VERSION 5.8 ;
BUSBITCHARS "[]" ;
DIVIDERCHAR "/" ;
UNITS
    DATABASE MICRONS 1000 ;
END UNITS

VIA PLL_RING_DCO_PHYS_via1_2_2200_440_1_5_410_410
  VIARULE via1Array ;
  CUTSIZE 0.19 0.19 ;
  LAYERS Metal1 Via1 Metal2 ;
  CUTSPACING 0.22 0.22 ;
  ENCLOSURE 0.05 0.125 0.005 0.05 ;
  ROWCOL 1 5 ;
END PLL_RING_DCO_PHYS_via1_2_2200_440_1_5_410_410

VIA PLL_RING_DCO_PHYS_via2_3_2200_440_1_5_410_410
  VIARULE via2Array ;
  CUTSIZE 0.19 0.19 ;
  LAYERS Metal2 Via2 Metal3 ;
  CUTSPACING 0.22 0.22 ;
  ENCLOSURE 0.005 0.05 0.05 0.005 ;
  ROWCOL 1 5 ;
END PLL_RING_DCO_PHYS_via2_3_2200_440_1_5_410_410

VIA PLL_RING_DCO_PHYS_via3_4_2200_440_1_5_410_410
  VIARULE via3Array ;
  CUTSIZE 0.19 0.19 ;
  LAYERS Metal3 Via3 Metal4 ;
  CUTSPACING 0.22 0.22 ;
  ENCLOSURE 0.05 0.005 0.005 0.05 ;
  ROWCOL 1 5 ;
END PLL_RING_DCO_PHYS_via3_4_2200_440_1_5_410_410

VIA PLL_RING_DCO_PHYS_via4_5_2200_440_1_5_410_410
  VIARULE via4Array ;
  CUTSIZE 0.19 0.19 ;
  LAYERS Metal4 Via4 Metal5 ;
  CUTSPACING 0.22 0.22 ;
  ENCLOSURE 0.005 0.05 0.05 0.005 ;
  ROWCOL 1 5 ;
END PLL_RING_DCO_PHYS_via4_5_2200_440_1_5_410_410

VIA PLL_RING_DCO_PHYS_via5_6_2200_440_1_2_840_840
  VIARULE viaTop1Array ;
  CUTSIZE 0.42 0.42 ;
  LAYERS Metal5 TopVia1 TopMetal1 ;
  CUTSPACING 0.42 0.42 ;
  ENCLOSURE 0.1 0.1 0.47 0.42 ;
  ROWCOL 1 2 ;
END PLL_RING_DCO_PHYS_via5_6_2200_440_1_2_840_840

VIA PLL_RING_DCO_PHYS_via6_7_5000_5000_2_2_1960_1960
  VIARULE viaTop2Array ;
  CUTSIZE 0.9 0.9 ;
  LAYERS TopMetal1 TopVia2 TopMetal2 ;
  CUTSPACING 1.06 1.06 ;
  ENCLOSURE 1.07 0.5 0.5 1.07 ;
  ROWCOL 2 2 ;
END PLL_RING_DCO_PHYS_via6_7_5000_5000_2_2_1960_1960

VIA PLL_RING_DCO_PHYS_via6_7_5000_2200_1_2_1960_1960
  VIARULE viaTop2Array ;
  CUTSIZE 0.9 0.9 ;
  LAYERS TopMetal1 TopVia2 TopMetal2 ;
  CUTSPACING 1.06 1.06 ;
  ENCLOSURE 1.07 0.5 0.5 0.65 ;
  ROWCOL 1 2 ;
END PLL_RING_DCO_PHYS_via6_7_5000_2200_1_2_1960_1960

VIA PLL_RING_DCO_PHYS_via6_7_2200_5000_2_1_1960_1960
  VIARULE viaTop2Array ;
  CUTSIZE 0.9 0.9 ;
  LAYERS TopMetal1 TopVia2 TopMetal2 ;
  CUTSPACING 1.06 1.06 ;
  ENCLOSURE 0.65 0.5 0.5 1.07 ;
  ROWCOL 2 1 ;
END PLL_RING_DCO_PHYS_via6_7_2200_5000_2_1_1960_1960

VIA PLL_RING_DCO_PHYS_via6_7_2200_2200_1_1_1960_1960
  VIARULE viaTop2Array ;
  CUTSIZE 0.9 0.9 ;
  LAYERS TopMetal1 TopVia2 TopMetal2 ;
  CUTSPACING 1.06 1.06 ;
  ENCLOSURE 0.65 0.5 0.5 0.65 ;
END PLL_RING_DCO_PHYS_via6_7_2200_2200_1_1_1960_1960

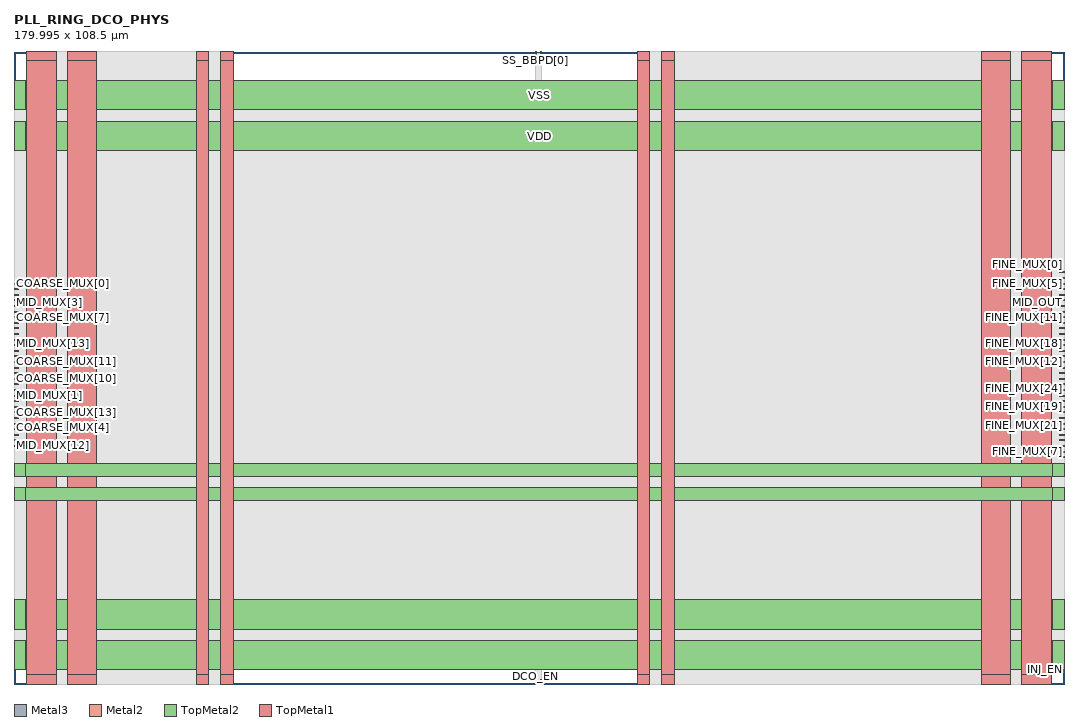
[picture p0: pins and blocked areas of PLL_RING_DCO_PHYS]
MACRO PLL_RING_DCO_PHYS
  FOREIGN PLL_RING_DCO_PHYS 0 0 ;
  CLASS BLOCK ;
  SIZE 179.995 BY 108.5 ;
  PIN COARSE_MUX[0]
    DIRECTION INPUT ;
    USE SIGNAL ;
    PORT
      LAYER Metal3 ;
        RECT  0 68.54 0.72 68.74 ;
    END
  END COARSE_MUX[0]
  PIN COARSE_MUX[10]
    DIRECTION INPUT ;
    USE SIGNAL ;
    PORT
      LAYER Metal3 ;
        RECT  0 52.22 0.72 52.42 ;
    END
  END COARSE_MUX[10]
  PIN COARSE_MUX[11]
    DIRECTION INPUT ;
    USE SIGNAL ;
    PORT
      LAYER Metal3 ;
        RECT  0 55.1 0.72 55.3 ;
    END
  END COARSE_MUX[11]
  PIN COARSE_MUX[12]
    DIRECTION INPUT ;
    USE SIGNAL ;
    PORT
      LAYER Metal3 ;
        RECT  0 56.06 0.72 56.26 ;
    END
  END COARSE_MUX[12]
  PIN COARSE_MUX[13]
    DIRECTION INPUT ;
    USE SIGNAL ;
    PORT
      LAYER Metal3 ;
        RECT  0 46.46 0.72 46.66 ;
    END
  END COARSE_MUX[13]
  PIN COARSE_MUX[14]
    DIRECTION INPUT ;
    USE SIGNAL ;
    PORT
      LAYER Metal3 ;
        RECT  0 53.18 0.72 53.38 ;
    END
  END COARSE_MUX[14]
  PIN COARSE_MUX[1]
    DIRECTION INPUT ;
    USE SIGNAL ;
    PORT
      LAYER Metal3 ;
        RECT  0 45.5 0.72 45.7 ;
    END
  END COARSE_MUX[1]
  PIN COARSE_MUX[2]
    DIRECTION INPUT ;
    USE SIGNAL ;
    PORT
      LAYER Metal3 ;
        RECT  0 58.94 0.72 59.14 ;
    END
  END COARSE_MUX[2]
  PIN COARSE_MUX[3]
    DIRECTION INPUT ;
    USE SIGNAL ;
    PORT
      LAYER Metal3 ;
        RECT  0 59.9 0.72 60.1 ;
    END
  END COARSE_MUX[3]
  PIN COARSE_MUX[4]
    DIRECTION INPUT ;
    USE SIGNAL ;
    PORT
      LAYER Metal3 ;
        RECT  0 42.62 0.72 42.82 ;
    END
  END COARSE_MUX[4]
  PIN COARSE_MUX[5]
    DIRECTION INPUT ;
    USE SIGNAL ;
    PORT
      LAYER Metal3 ;
        RECT  0 60.86 0.72 61.06 ;
    END
  END COARSE_MUX[5]
  PIN COARSE_MUX[6]
    DIRECTION INPUT ;
    USE SIGNAL ;
    PORT
      LAYER Metal3 ;
        RECT  0 50.3 0.72 50.5 ;
    END
  END COARSE_MUX[6]
  PIN COARSE_MUX[7]
    DIRECTION INPUT ;
    USE SIGNAL ;
    PORT
      LAYER Metal3 ;
        RECT  0 62.78 0.72 62.98 ;
    END
  END COARSE_MUX[7]
  PIN COARSE_MUX[8]
    DIRECTION INPUT ;
    USE SIGNAL ;
    PORT
      LAYER Metal3 ;
        RECT  0 51.26 0.72 51.46 ;
    END
  END COARSE_MUX[8]
  PIN COARSE_MUX[9]
    DIRECTION INPUT ;
    USE SIGNAL ;
    PORT
      LAYER Metal3 ;
        RECT  0 63.74 0.72 63.94 ;
    END
  END COARSE_MUX[9]
  PIN DCO_EN
    DIRECTION INPUT ;
    USE SIGNAL ;
    PORT
      LAYER Metal2 ;
        RECT  89.36 0 89.56 0.72 ;
    END
  END DCO_EN
  PIN FINE_MUX[0]
    DIRECTION INPUT ;
    USE SIGNAL ;
    PORT
      LAYER Metal3 ;
        RECT  179.275 70.46 179.995 70.66 ;
    END
  END FINE_MUX[0]
  PIN FINE_MUX[10]
    DIRECTION INPUT ;
    USE SIGNAL ;
    PORT
      LAYER Metal3 ;
        RECT  179.275 54.14 179.995 54.34 ;
    END
  END FINE_MUX[10]
  PIN FINE_MUX[11]
    DIRECTION INPUT ;
    USE SIGNAL ;
    PORT
      LAYER Metal3 ;
        RECT  179.275 62.78 179.995 62.98 ;
    END
  END FINE_MUX[11]
  PIN FINE_MUX[12]
    DIRECTION INPUT ;
    USE SIGNAL ;
    PORT
      LAYER Metal3 ;
        RECT  179.275 55.1 179.995 55.3 ;
    END
  END FINE_MUX[12]
  PIN FINE_MUX[13]
    DIRECTION INPUT ;
    USE SIGNAL ;
    PORT
      LAYER Metal3 ;
        RECT  179.275 52.22 179.995 52.42 ;
    END
  END FINE_MUX[13]
  PIN FINE_MUX[14]
    DIRECTION INPUT ;
    USE SIGNAL ;
    PORT
      LAYER Metal3 ;
        RECT  179.275 51.26 179.995 51.46 ;
    END
  END FINE_MUX[14]
  PIN FINE_MUX[15]
    DIRECTION INPUT ;
    USE SIGNAL ;
    PORT
      LAYER Metal3 ;
        RECT  179.275 50.3 179.995 50.5 ;
    END
  END FINE_MUX[15]
  PIN FINE_MUX[16]
    DIRECTION INPUT ;
    USE SIGNAL ;
    PORT
      LAYER Metal3 ;
        RECT  179.275 63.74 179.995 63.94 ;
    END
  END FINE_MUX[16]
  PIN FINE_MUX[17]
    DIRECTION INPUT ;
    USE SIGNAL ;
    PORT
      LAYER Metal3 ;
        RECT  179.275 67.58 179.995 67.78 ;
    END
  END FINE_MUX[17]
  PIN FINE_MUX[18]
    DIRECTION INPUT ;
    USE SIGNAL ;
    PORT
      LAYER Metal3 ;
        RECT  179.275 57.02 179.995 57.22 ;
    END
  END FINE_MUX[18]
  PIN FINE_MUX[19]
    DIRECTION INPUT ;
    USE SIGNAL ;
    PORT
      LAYER Metal3 ;
        RECT  179.275 47.42 179.995 47.62 ;
    END
  END FINE_MUX[19]
  PIN FINE_MUX[1]
    DIRECTION INPUT ;
    USE SIGNAL ;
    PORT
      LAYER Metal3 ;
        RECT  179.275 58.94 179.995 59.14 ;
    END
  END FINE_MUX[1]
  PIN FINE_MUX[20]
    DIRECTION INPUT ;
    USE SIGNAL ;
    PORT
      LAYER Metal3 ;
        RECT  179.275 64.7 179.995 64.9 ;
    END
  END FINE_MUX[20]
  PIN FINE_MUX[21]
    DIRECTION INPUT ;
    USE SIGNAL ;
    PORT
      LAYER Metal3 ;
        RECT  179.275 45.5 179.995 45.7 ;
    END
  END FINE_MUX[21]
  PIN FINE_MUX[22]
    DIRECTION INPUT ;
    USE SIGNAL ;
    PORT
      LAYER Metal3 ;
        RECT  179.275 44.54 179.995 44.74 ;
    END
  END FINE_MUX[22]
  PIN FINE_MUX[23]
    DIRECTION INPUT ;
    USE SIGNAL ;
    PORT
      LAYER Metal3 ;
        RECT  179.275 57.98 179.995 58.18 ;
    END
  END FINE_MUX[23]
  PIN FINE_MUX[24]
    DIRECTION INPUT ;
    USE SIGNAL ;
    PORT
      LAYER Metal3 ;
        RECT  179.275 49.34 179.995 49.54 ;
    END
  END FINE_MUX[24]
  PIN FINE_MUX[25]
    DIRECTION INPUT ;
    USE SIGNAL ;
    PORT
      LAYER Metal3 ;
        RECT  179.275 42.62 179.995 42.82 ;
    END
  END FINE_MUX[25]
  PIN FINE_MUX[26]
    DIRECTION INPUT ;
    USE SIGNAL ;
    PORT
      LAYER Metal3 ;
        RECT  179.275 61.82 179.995 62.02 ;
    END
  END FINE_MUX[26]
  PIN FINE_MUX[27]
    DIRECTION INPUT ;
    USE SIGNAL ;
    PORT
      LAYER Metal3 ;
        RECT  179.275 65.66 179.995 65.86 ;
    END
  END FINE_MUX[27]
  PIN FINE_MUX[28]
    DIRECTION INPUT ;
    USE SIGNAL ;
    PORT
      LAYER Metal3 ;
        RECT  179.275 69.5 179.995 69.7 ;
    END
  END FINE_MUX[28]
  PIN FINE_MUX[29]
    DIRECTION INPUT ;
    USE SIGNAL ;
    PORT
      LAYER Metal3 ;
        RECT  179.275 46.46 179.995 46.66 ;
    END
  END FINE_MUX[29]
  PIN FINE_MUX[2]
    DIRECTION INPUT ;
    USE SIGNAL ;
    PORT
      LAYER Metal3 ;
        RECT  179.275 53.18 179.995 53.38 ;
    END
  END FINE_MUX[2]
  PIN FINE_MUX[30]
    DIRECTION INPUT ;
    USE SIGNAL ;
    PORT
      LAYER Metal3 ;
        RECT  179.275 59.9 179.995 60.1 ;
    END
  END FINE_MUX[30]
  PIN FINE_MUX[3]
    DIRECTION INPUT ;
    USE SIGNAL ;
    PORT
      LAYER Metal3 ;
        RECT  179.275 41.66 179.995 41.86 ;
    END
  END FINE_MUX[3]
  PIN FINE_MUX[4]
    DIRECTION INPUT ;
    USE SIGNAL ;
    PORT
      LAYER Metal3 ;
        RECT  179.275 43.58 179.995 43.78 ;
    END
  END FINE_MUX[4]
  PIN FINE_MUX[5]
    DIRECTION INPUT ;
    USE SIGNAL ;
    PORT
      LAYER Metal3 ;
        RECT  179.275 68.54 179.995 68.74 ;
    END
  END FINE_MUX[5]
  PIN FINE_MUX[6]
    DIRECTION INPUT ;
    USE SIGNAL ;
    PORT
      LAYER Metal3 ;
        RECT  179.275 60.86 179.995 61.06 ;
    END
  END FINE_MUX[6]
  PIN FINE_MUX[7]
    DIRECTION INPUT ;
    USE SIGNAL ;
    PORT
      LAYER Metal3 ;
        RECT  179.275 39.74 179.995 39.94 ;
    END
  END FINE_MUX[7]
  PIN FINE_MUX[8]
    DIRECTION INPUT ;
    USE SIGNAL ;
    PORT
      LAYER Metal3 ;
        RECT  179.275 38.78 179.995 38.98 ;
    END
  END FINE_MUX[8]
  PIN FINE_MUX[9]
    DIRECTION INPUT ;
    USE SIGNAL ;
    PORT
      LAYER Metal3 ;
        RECT  179.275 56.06 179.995 56.26 ;
    END
  END FINE_MUX[9]
  PIN INJ_EN
    DIRECTION INPUT ;
    USE SIGNAL ;
    PORT
      LAYER Metal3 ;
        RECT  179.275 2.3 179.995 2.5 ;
    END
  END INJ_EN
  PIN MID_MUX[0]
    DIRECTION INPUT ;
    USE SIGNAL ;
    PORT
      LAYER Metal3 ;
        RECT  0 64.7 0.72 64.9 ;
    END
  END MID_MUX[0]
  PIN MID_MUX[10]
    DIRECTION INPUT ;
    USE SIGNAL ;
    PORT
      LAYER Metal3 ;
        RECT  0 57.98 0.72 58.18 ;
    END
  END MID_MUX[10]
  PIN MID_MUX[11]
    DIRECTION INPUT ;
    USE SIGNAL ;
    PORT
      LAYER Metal3 ;
        RECT  0 44.54 0.72 44.74 ;
    END
  END MID_MUX[11]
  PIN MID_MUX[12]
    DIRECTION INPUT ;
    USE SIGNAL ;
    PORT
      LAYER Metal3 ;
        RECT  0 40.7 0.72 40.9 ;
    END
  END MID_MUX[12]
  PIN MID_MUX[13]
    DIRECTION INPUT ;
    USE SIGNAL ;
    PORT
      LAYER Metal3 ;
        RECT  0 57.02 0.72 57.22 ;
    END
  END MID_MUX[13]
  PIN MID_MUX[14]
    DIRECTION INPUT ;
    USE SIGNAL ;
    PORT
      LAYER Metal3 ;
        RECT  0 65.66 0.72 65.86 ;
    END
  END MID_MUX[14]
  PIN MID_MUX[1]
    DIRECTION INPUT ;
    USE SIGNAL ;
    PORT
      LAYER Metal3 ;
        RECT  0 49.34 0.72 49.54 ;
    END
  END MID_MUX[1]
  PIN MID_MUX[2]
    DIRECTION INPUT ;
    USE SIGNAL ;
    PORT
      LAYER Metal3 ;
        RECT  0 47.42 0.72 47.62 ;
    END
  END MID_MUX[2]
  PIN MID_MUX[3]
    DIRECTION INPUT ;
    USE SIGNAL ;
    PORT
      LAYER Metal3 ;
        RECT  0 66.62 0.72 66.82 ;
    END
  END MID_MUX[3]
  PIN MID_MUX[4]
    DIRECTION INPUT ;
    USE SIGNAL ;
    PORT
      LAYER Metal3 ;
        RECT  0 67.58 0.72 67.78 ;
    END
  END MID_MUX[4]
  PIN MID_MUX[5]
    DIRECTION INPUT ;
    USE SIGNAL ;
    PORT
      LAYER Metal3 ;
        RECT  0 48.38 0.72 48.58 ;
    END
  END MID_MUX[5]
  PIN MID_MUX[6]
    DIRECTION INPUT ;
    USE SIGNAL ;
    PORT
      LAYER Metal3 ;
        RECT  0 43.58 0.72 43.78 ;
    END
  END MID_MUX[6]
  PIN MID_MUX[7]
    DIRECTION INPUT ;
    USE SIGNAL ;
    PORT
      LAYER Metal3 ;
        RECT  0 54.14 0.72 54.34 ;
    END
  END MID_MUX[7]
  PIN MID_MUX[8]
    DIRECTION INPUT ;
    USE SIGNAL ;
    PORT
      LAYER Metal3 ;
        RECT  0 61.82 0.72 62.02 ;
    END
  END MID_MUX[8]
  PIN MID_MUX[9]
    DIRECTION INPUT ;
    USE SIGNAL ;
    PORT
      LAYER Metal3 ;
        RECT  0 41.66 0.72 41.86 ;
    END
  END MID_MUX[9]
  PIN MID_OUT
    DIRECTION OUTPUT ;
    USE SIGNAL ;
    PORT
      LAYER Metal3 ;
        RECT  179.275 66.62 179.995 66.82 ;
    END
  END MID_OUT
  PIN OUT
    DIRECTION OUTPUT ;
    USE SIGNAL ;
    PORT
      LAYER Metal3 ;
        RECT  179.275 48.38 179.995 48.58 ;
    END
  END OUT
  PIN INJ_EDGE
    DIRECTION OUTPUT ;
    USE SIGNAL ;
    PORT
      LAYER Metal3 ;
        RECT  179.275 40.7 179.995 40.9 ;
    END
  END INJ_EDGE
  PIN REF
    DIRECTION INPUT ;
    USE SIGNAL ;
    PORT
      LAYER Metal2 ;
        RECT  90.2 0 90.4 0.72 ;
    END
  END REF
  PIN SS_BBPD[0]
    DIRECTION OUTPUT ;
    USE SIGNAL ;
    PORT
      LAYER Metal2 ;
        RECT  89.36 107.78 89.56 108.5 ;
    END
  END SS_BBPD[0]
  PIN SS_BBPD[1]
    DIRECTION OUTPUT ;
    USE SIGNAL ;
    PORT
      LAYER Metal2 ;
        RECT  90.2 107.78 90.4 108.5 ;
    END
  END SS_BBPD[1]
  PIN VSS
    DIRECTION INOUT ;
    USE GROUND ;
    PORT
      LAYER TopMetal2 ;
        RECT  177.995 35.6 179.995 37.8 ;
        RECT  0 35.6 2 37.8 ;
        RECT  0 35.6 179.995 37.8 ;
      LAYER TopMetal1 ;
        RECT  111.02 106.86 113.22 108.5 ;
        RECT  111.02 0 113.22 1.64 ;
        RECT  111.02 0 113.22 108.5 ;
        RECT  35.42 106.86 37.62 108.5 ;
        RECT  35.42 0 37.62 1.64 ;
        RECT  35.42 0 37.62 108.5 ;
      LAYER TopMetal2 ;
        RECT  177.995 98.44 179.995 103.44 ;
        RECT  0 98.44 2 103.44 ;
        RECT  0 98.44 179.995 103.44 ;
        RECT  177.995 2.4 179.995 7.4 ;
        RECT  0 2.4 2 7.4 ;
        RECT  0 2.4 179.995 7.4 ;
      LAYER TopMetal1 ;
        RECT  172.78 106.86 177.78 108.5 ;
        RECT  172.78 0 177.78 1.64 ;
        RECT  172.78 0 177.78 108.5 ;
        RECT  2.22 106.86 7.22 108.5 ;
        RECT  2.22 0 7.22 1.64 ;
        RECT  2.22 0 7.22 108.5 ;
    END
  END VSS
  PIN VDD
    DIRECTION INOUT ;
    USE POWER ;
    PORT
      LAYER TopMetal2 ;
        RECT  177.995 31.4 179.995 33.6 ;
        RECT  0 31.4 2 33.6 ;
        RECT  0 31.4 179.995 33.6 ;
      LAYER TopMetal1 ;
        RECT  106.82 106.86 109.02 108.5 ;
        RECT  106.82 0 109.02 1.64 ;
        RECT  106.82 0 109.02 108.5 ;
        RECT  31.22 106.86 33.42 108.5 ;
        RECT  31.22 0 33.42 1.64 ;
        RECT  31.22 0 33.42 108.5 ;
      LAYER TopMetal2 ;
        RECT  177.995 91.44 179.995 96.44 ;
        RECT  0 91.44 2 96.44 ;
        RECT  0 91.44 179.995 96.44 ;
        RECT  177.995 9.4 179.995 14.4 ;
        RECT  0 9.4 2 14.4 ;
        RECT  0 9.4 179.995 14.4 ;
      LAYER TopMetal1 ;
        RECT  165.78 106.86 170.78 108.5 ;
        RECT  165.78 0 170.78 1.64 ;
        RECT  165.78 0 170.78 108.5 ;
        RECT  9.22 106.86 14.22 108.5 ;
        RECT  9.22 0 14.22 1.64 ;
        RECT  9.22 0 14.22 108.5 ;
    END
  END VDD
  OBS
    LAYER Metal1 ;
     RECT  18.72 18.68 161.28 87.16 ;
    LAYER Metal2 ;
     RECT  89.36 0.48 90.4 6.14 ;
     RECT  89.36 6.14 94.6 6.34 ;
     RECT  111.2 18.755 113.04 20.06 ;
     RECT  60.38 20.545 60.58 20.55 ;
     RECT  130.94 20.545 131.14 20.55 ;
     RECT  60.38 20.55 63.52 20.78 ;
     RECT  60.38 20.78 79.69 20.895 ;
     RECT  89.78 6.34 94.6 20.895 ;
     RECT  111.2 20.06 117.28 20.915 ;
     RECT  144.38 20.955 144.58 21.51 ;
     RECT  144.38 21.51 145.42 21.98 ;
     RECT  60.38 20.895 94.6 22.46 ;
     RECT  130.94 20.55 134.08 22.46 ;
     RECT  20.9 20.54 22.78 22.535 ;
     RECT  35.6 18.755 37.44 22.535 ;
     RECT  110.36 20.915 117.28 22.535 ;
     RECT  59.54 22.46 94.6 22.94 ;
     RECT  53.24 22.94 94.6 22.95 ;
     RECT  107 22.535 117.28 22.95 ;
     RECT  128.84 22.46 134.08 22.95 ;
     RECT  143.96 21.98 145.42 22.95 ;
     RECT  20.9 22.535 37.44 23.43 ;
     RECT  53.24 22.95 117.28 23.43 ;
     RECT  20.9 23.43 117.28 23.9 ;
     RECT  128.84 22.95 145.42 23.9 ;
     RECT  128.84 23.9 148.36 24.38 ;
     RECT  20.06 23.9 117.28 24.675 ;
     RECT  128.42 24.38 149.2 25.34 ;
     RECT  19.64 24.675 117.28 27.26 ;
     RECT  19.64 27.26 117.7 31.58 ;
     RECT  128.42 25.34 150.46 31.58 ;
     RECT  19.64 31.58 150.46 32.06 ;
     RECT  19.22 32.06 150.46 34.94 ;
     RECT  19.22 34.94 160.54 35.14 ;
     RECT  19.22 35.14 160.12 38.98 ;
     RECT  171.26 35.9 171.46 39.94 ;
     RECT  170.42 42.14 170.62 45.7 ;
     RECT  19.22 38.98 159.01 46.94 ;
     RECT  4.94 42.62 5.14 51.74 ;
     RECT  18.8 46.94 159.01 56.26 ;
     RECT  4.94 51.74 5.98 58.18 ;
     RECT  19.22 56.26 159.01 59.9 ;
     RECT  4.94 58.18 5.14 62.5 ;
     RECT  19.22 59.9 160.54 62.5 ;
     RECT  171.26 61.34 171.46 63.94 ;
     RECT  19.22 62.5 160.12 69.7 ;
     RECT  20.06 69.7 160.12 70.65 ;
     RECT  21.32 70.65 160.12 73.34 ;
     RECT  21.32 73.34 160.54 73.54 ;
     RECT  21.32 73.54 159.49 74.02 ;
     RECT  159.29 74.02 159.49 74.255 ;
     RECT  21.32 74.02 140.8 77.38 ;
     RECT  21.32 77.38 126.94 78.34 ;
     RECT  21.32 78.34 71.55 80.455 ;
     RECT  21.15 80.455 71.55 80.54 ;
     RECT  21.11 80.54 71.55 80.55 ;
     RECT  19.64 80.55 71.55 81.12 ;
     RECT  20.06 81.12 71.55 81.7 ;
     RECT  82.43 78.34 126.94 82.18 ;
     RECT  20.06 81.7 70.66 82.56 ;
     RECT  20.06 82.56 64.36 82.66 ;
     RECT  83.27 82.18 126.94 82.66 ;
     RECT  31.4 82.66 50.5 83.13 ;
     RECT  31.4 83.13 38.74 83.14 ;
     RECT  31.4 83.14 37.44 83.305 ;
     RECT  49.46 83.13 50.5 84.1 ;
     RECT  49.46 84.1 49.66 85.06 ;
     RECT  83.27 82.66 126.31 85.06 ;
     RECT  83.27 85.06 97.96 85.3 ;
     RECT  35.6 83.305 37.44 87.085 ;
     RECT  111.2 85.06 113.04 87.085 ;
     RECT  90.2 85.3 97.96 100.42 ;
     RECT  90.2 100.42 90.4 100.7 ;
     RECT  89.36 100.7 90.4 108 ;
    LAYER Metal3 ;
     RECT  0.42 40.7 12.5 68.74 ;
     RECT  12.5 40.7 20.06 69.22 ;
     RECT  20.06 24.38 20.9 70.18 ;
     RECT  19.64 81.02 21.15 81.22 ;
     RECT  20.9 23.9 22.095 70.18 ;
     RECT  21.15 80.54 22.095 81.22 ;
     RECT  22.095 23.9 23.42 81.22 ;
     RECT  23.42 23.42 31.355 81.22 ;
     RECT  31.355 22.58 35.555 83.26 ;
     RECT  35.555 18.8 37.485 87.04 ;
     RECT  37.485 23.9 40.42 82.66 ;
     RECT  40.42 23.9 53.86 81.7 ;
     RECT  53.86 23.9 56.77 25.06 ;
     RECT  56.77 23.9 56.8 24.1 ;
     RECT  53.86 34.94 63.1 81.7 ;
     RECT  60.38 21.02 63.52 21.7 ;
     RECT  63.1 35.9 64.16 81.7 ;
     RECT  63.52 21.5 65.83 21.7 ;
     RECT  67.52 21.98 67.94 22.18 ;
     RECT  64.16 35.9 70.66 82.66 ;
     RECT  67.94 21.98 71.08 23.62 ;
     RECT  70.66 35.9 71.55 81.7 ;
     RECT  71.08 22.94 73.82 23.62 ;
     RECT  73.82 22.94 74.66 24.58 ;
     RECT  71.55 35.9 74.66 76.42 ;
     RECT  74.66 22.94 77.38 76.42 ;
     RECT  77.38 22.94 78.22 74.02 ;
     RECT  78.22 22.94 82.63 24.58 ;
     RECT  78.22 37.82 82.63 74.02 ;
     RECT  82.63 22.94 86.84 23.62 ;
     RECT  82.63 37.82 89.56 73.54 ;
     RECT  89.36 100.22 89.56 100.9 ;
     RECT  89.56 100.22 90.2 100.42 ;
     RECT  86.84 21.98 90.4 23.62 ;
     RECT  89.56 37.82 90.4 69.7 ;
     RECT  90.4 37.82 90.82 66.82 ;
     RECT  90.4 22.94 92.29 23.62 ;
     RECT  92.29 23.42 93.14 23.62 ;
     RECT  90.82 37.82 93.14 46.66 ;
     RECT  90.82 61.34 94.18 66.82 ;
     RECT  89.36 6.14 94.6 6.34 ;
     RECT  90.2 94.46 96.7 100.42 ;
     RECT  93.14 23.42 97.12 46.66 ;
     RECT  96.7 100.22 97.96 100.42 ;
     RECT  98.18 84.86 100.28 85.06 ;
     RECT  100.28 84.38 101.32 85.06 ;
     RECT  97.12 39.26 101.54 46.66 ;
     RECT  94.18 61.34 101.54 66.34 ;
     RECT  101.54 39.26 104.48 66.34 ;
     RECT  104.48 39.26 104.9 74.02 ;
     RECT  101.32 84.38 104.9 84.58 ;
     RECT  97.12 23.42 106.955 24.58 ;
     RECT  104.9 39.26 106.955 84.58 ;
     RECT  106.955 22.58 110.36 84.58 ;
     RECT  110.36 21.98 111.155 84.58 ;
     RECT  111.155 18.8 113.085 87.04 ;
     RECT  113.085 37.82 113.5 71.14 ;
     RECT  113.085 21.98 115.18 24.58 ;
     RECT  113.085 81.5 115.81 85.06 ;
     RECT  115.18 24.38 117.28 24.58 ;
     RECT  113.5 37.82 120.64 66.34 ;
     RECT  120.64 37.82 123.38 53.86 ;
     RECT  120.64 64.7 124.22 66.34 ;
     RECT  123.38 35.9 125.48 53.86 ;
     RECT  115.81 84.38 126.31 85.06 ;
     RECT  124.22 64.7 129.595 72.58 ;
     RECT  125.48 31.58 132.2 53.86 ;
     RECT  129.595 64.7 132.2 77.38 ;
     RECT  132.2 31.58 133.03 77.38 ;
     RECT  130.94 21.02 134.08 21.22 ;
     RECT  133.03 31.58 136.315 31.78 ;
     RECT  136.315 23.42 139.12 31.78 ;
     RECT  133.03 42.14 140.8 77.38 ;
     RECT  140.8 42.14 143.415 74.02 ;
     RECT  139.12 23.42 143.96 27.46 ;
     RECT  143.96 21.98 145.42 27.46 ;
     RECT  145.42 27.26 147.1 27.46 ;
     RECT  143.415 39.74 148.79 74.02 ;
     RECT  148.79 37.82 152.57 74.02 ;
     RECT  152.57 35.42 154.38 74.02 ;
     RECT  154.38 35.9 159.49 74.02 ;
     RECT  159.49 35.9 171.46 70.66 ;
     RECT  171.46 38.78 179.34 70.66 ;
    LAYER Metal4 ;
     RECT  35.6 18.755 37.44 22.535 ;
     RECT  111.2 18.755 113.04 22.535 ;
     RECT  31.4 22.535 37.44 39.74 ;
     RECT  90.62 40.23 90.82 40.8 ;
     RECT  170 40.23 170.2 40.8 ;
     RECT  170.42 41.66 172.3 41.86 ;
     RECT  19.64 44.54 19.84 47.62 ;
     RECT  31.4 39.74 46.3 51.46 ;
     RECT  56.18 51.26 56.38 53.86 ;
     RECT  136.82 57.51 137.02 58.08 ;
     RECT  170 57.51 170.2 58.08 ;
     RECT  31.4 51.46 37.44 83.305 ;
     RECT  107 22.535 113.04 83.305 ;
     RECT  35.6 83.305 37.44 87.085 ;
     RECT  111.2 83.305 113.04 87.085 ;
    LAYER Metal5 ;
     RECT  31.355 22.37 35.555 83.47 ;
     RECT  35.555 18.59 37.485 87.25 ;
     RECT  90.62 40.7 106.955 40.9 ;
     RECT  106.955 22.37 111.155 83.47 ;
     RECT  111.155 18.59 113.085 87.25 ;
     RECT  113.085 40.7 170.2 40.9 ;
     RECT  136.82 57.98 170.2 58.18 ;
    LAYER TopMetal1 ;
     RECT  2.22 0 37.62 108.5 ;
     RECT  106.82 0 177.78 108.5 ;
    LAYER TopMetal2 ;
     RECT  0 2.4 179.995 103.44 ;
  END
END PLL_RING_DCO_PHYS
END LIBRARY
